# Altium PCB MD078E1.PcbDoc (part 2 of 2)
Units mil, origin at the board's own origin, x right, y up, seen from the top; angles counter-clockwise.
Board outline 4255 x 2850 mil, 4 copper layers (Top Layer, Ground, Power, Bottom Layer), stack 61.6 mil thick; 156 components, 78 nets, 386 pads, 392 vias.
Unrouted connection lines stored in the file: 8.

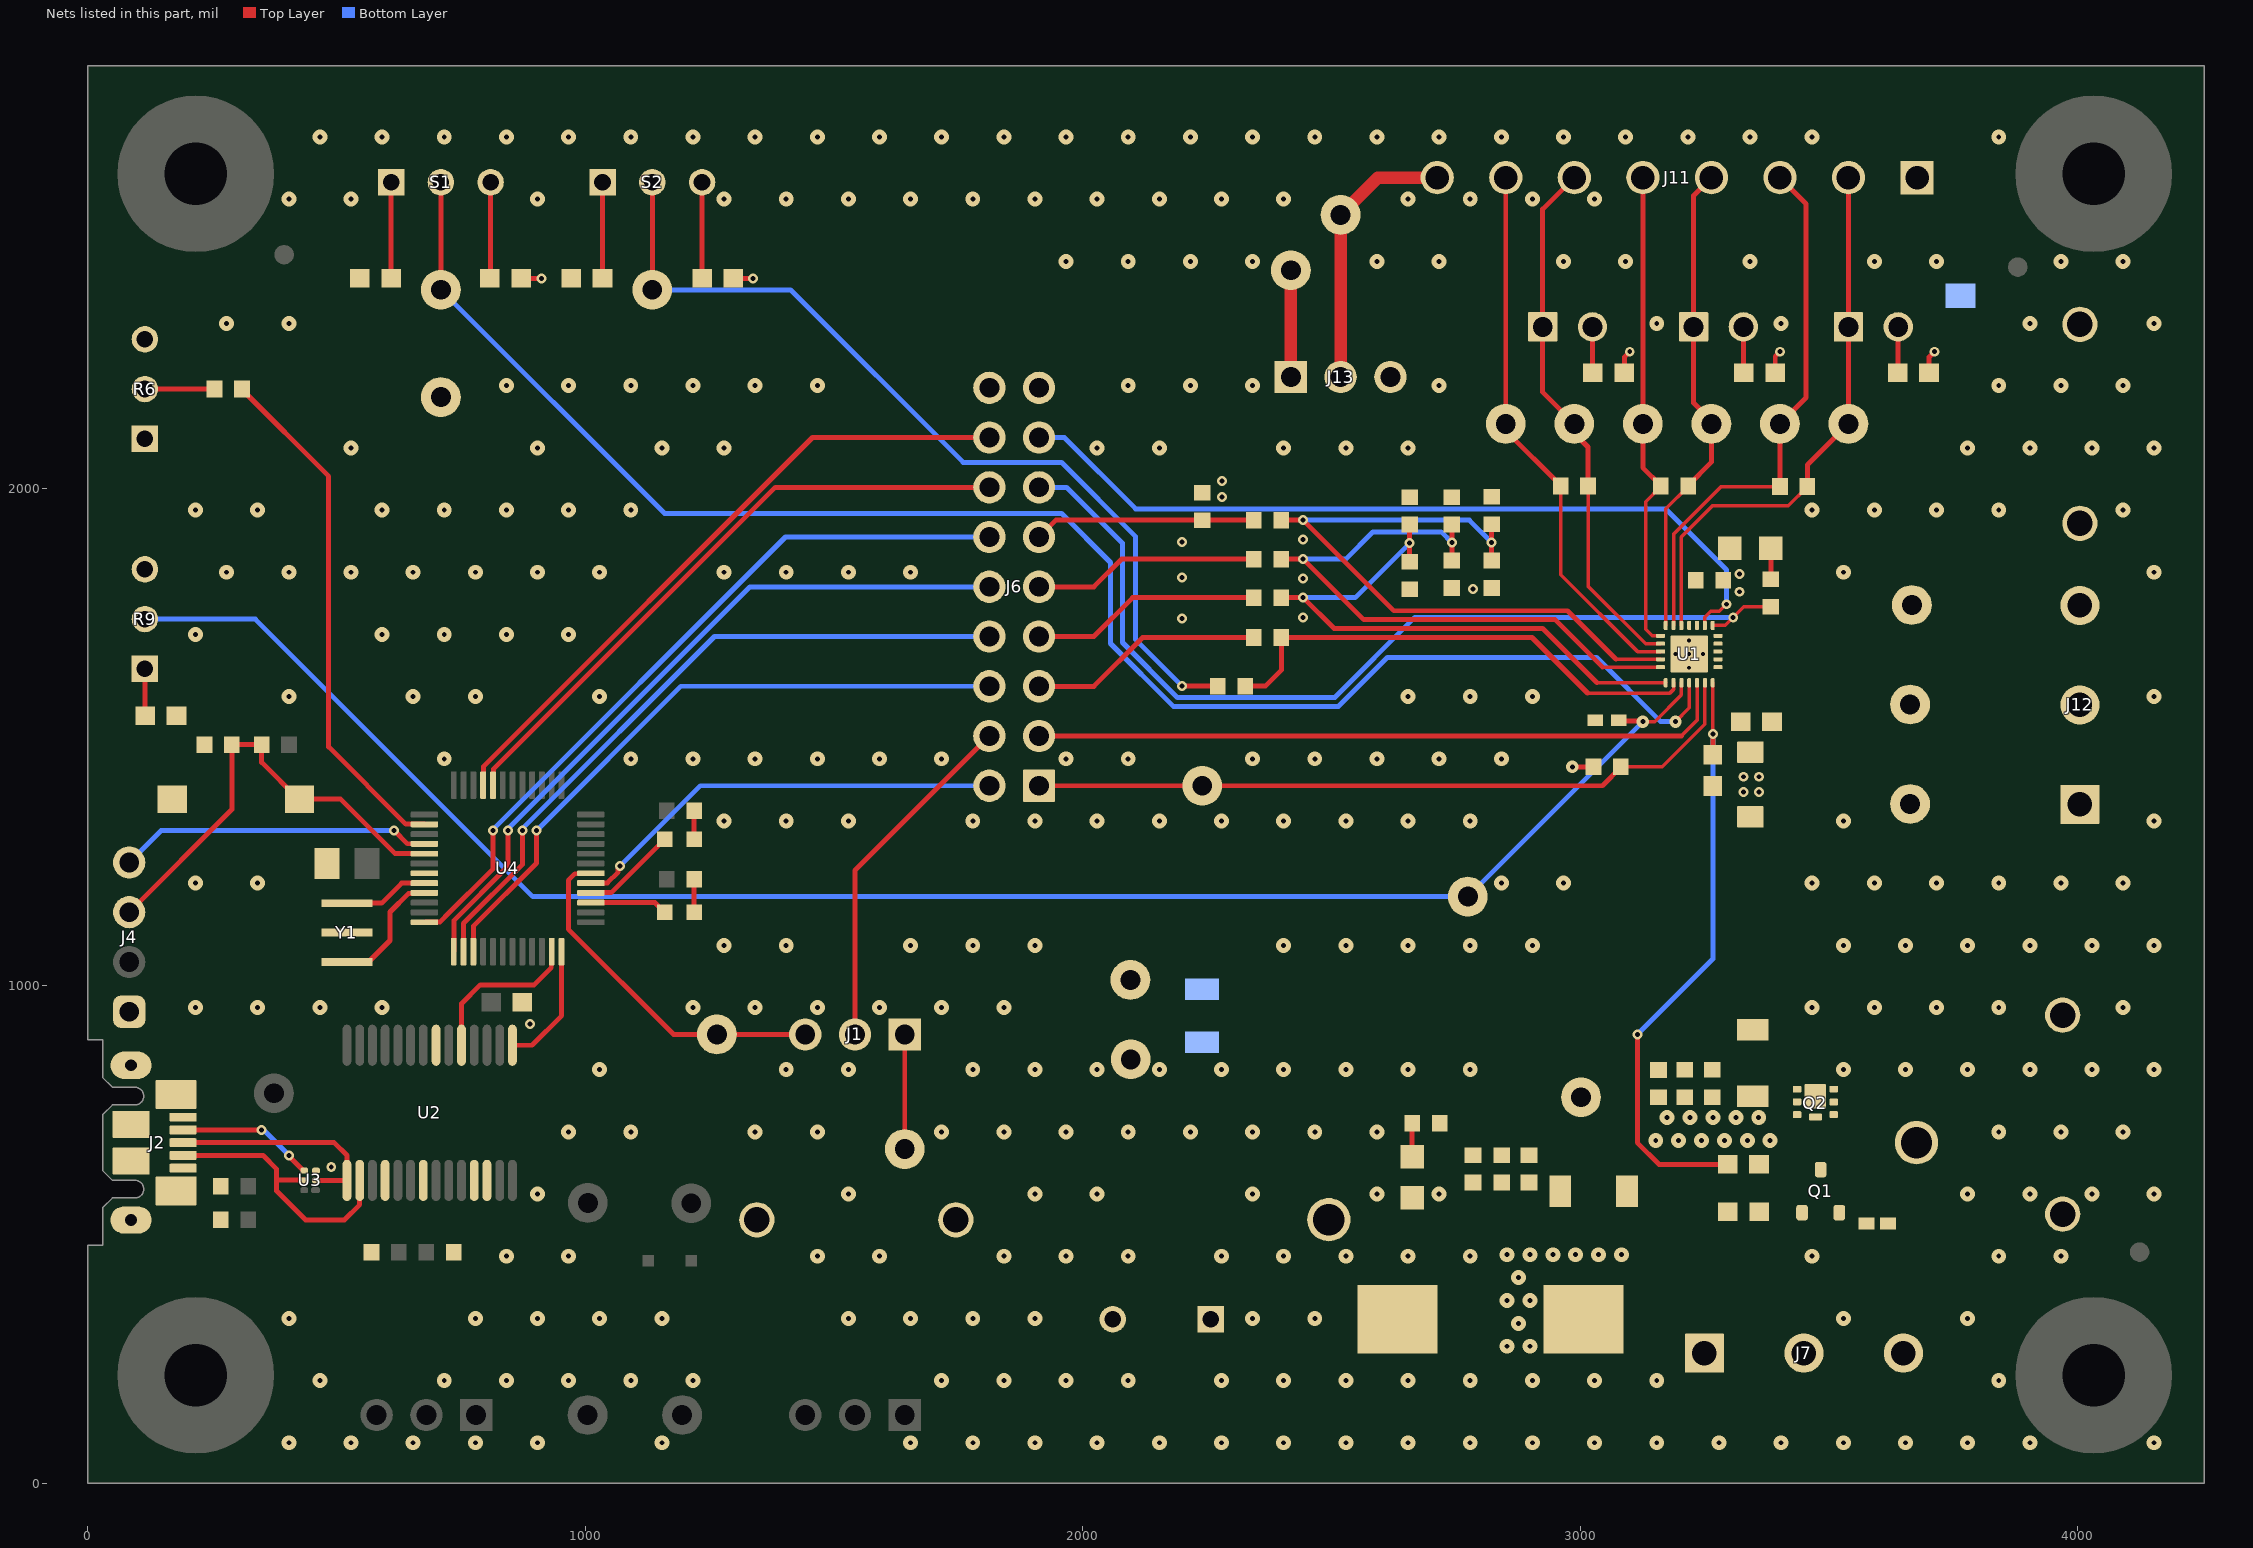
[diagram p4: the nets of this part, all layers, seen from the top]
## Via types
v1: diameter 30, hole 10, Top Layer to Bottom Layer, tented both sides, 335 vias
v2: diameter 20, hole 10, Top Layer to Bottom Layer, 30 vias
v3: diameter 20, hole 10, Top Layer to Bottom Layer, tented both sides, 19 vias
v4: diameter 19.68, hole 7.87, Top Layer to Bottom Layer, tented both sides, 5 vias
v5: diameter 25, hole 10, Top Layer to Bottom Layer, 3 vias

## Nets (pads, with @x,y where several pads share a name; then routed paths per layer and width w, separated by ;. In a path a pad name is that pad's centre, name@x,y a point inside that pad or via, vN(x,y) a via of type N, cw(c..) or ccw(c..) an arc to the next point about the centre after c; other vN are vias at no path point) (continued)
AGND: C1.2 C5.2 C6.2 C7.2 C8.1 C9.2 C10.2 C11.2 J2.5 J2.6 J2.7 J2.8 J2.9 J2.10 J2.11 J4.1 J6.17 J6.18 J11.1 NT1.1 R4.1 R5.1 R6.3 R15.1 R21.1 R22.1 R23.1 R32.1 S3.2 TP18.1 TP18.2 TP23.1 TP24.1 U1.16 U1.25 U2.7 U2.18 U2.21 U2.25 U2.26 U3.3 U4.7 Y1.2
  other v1: 404.27,81.7 529.27,81.7 654.27,81.7 779.27,81.7 904.27,81.7 1154.27,81.7 1654.27,81.7 1779.27,81.7 466.77,206.7 716.77,206.7 841.77,206.7 966.77,206.7 1091.77,206.7 1216.77,206.7 1716.77,206.7 1841.77,206.7 404.27,331.7 779.27,331.7 904.27,331.7 1029.27,331.7 1154.27,331.7 1529.27,331.7 1654.27,331.7 1779.27,331.7 841.77,456.7 966.77,456.7 1466.77,456.7 1591.77,456.7 1841.77,456.7 904.27,581.7 1529.27,581.7 966.77,706.7 1091.77,706.7 1341.77,706.7 1466.77,706.7 1716.77,706.7 1841.77,706.7 1029.27,831.7 1404.27,831.7 1529.27,831.7 1779.27,831.7 216.77,956.7 341.77,956.7 466.77,956.7 591.77,956.7 1216.77,956.7 1341.77,956.7 1466.77,956.7 1591.77,956.7 1716.77,956.7 1841.77,956.7 1279.27,1081.7 1404.27,1081.7 1654.27,1081.7 1779.27,1081.7 1904.27,1081.7 2404.27,1081.7 2529.27,1081.7 2654.27,1081.7 2779.27,1081.7 2904.27,1081.7 216.77,1206.7 341.77,1206.7 2841.77,1206.7 2966.77,1206.7 1279.27,1331.7 1404.27,1331.7 1529.27,1331.7 1779.27,1331.7 1904.27,1331.7 2029.27,1331.7 2154.27,1331.7 2279.27,1331.7 2404.27,1331.7 2529.27,1331.7 2654.27,1331.7 2779.27,1331.7 716.77,1456.7 1091.77,1456.7 1216.77,1456.7 1341.77,1456.7 1466.77,1456.7 1591.77,1456.7 1716.77,1456.7 1966.77,1456.7 2091.77,1456.7 2341.77,1456.7 2466.77,1456.7 2591.77,1456.7 2716.77,1456.7 2841.77,1456.7 404.27,1581.7 654.27,1581.7 779.27,1581.7 1029.27,1581.7 2654.27,1581.7 2779.27,1581.7 2904.27,1581.7 216.77,1706.7 591.77,1706.7 716.77,1706.7 841.77,1706.7 966.77,1706.7 279.27,1831.7 404.27,1831.7 529.27,1831.7 654.27,1831.7 779.27,1831.7 904.27,1831.7 1029.27,1831.7 1279.27,1831.7 1404.27,1831.7 1529.27,1831.7 1654.27,1831.7 216.77,1956.7 341.77,1956.7 591.77,1956.7 716.77,1956.7 841.77,1956.7 966.77,1956.7 1091.77,1956.7 3466.77,1956.7 529.27,2081.7 904.27,2081.7 1154.27,2081.7 1279.27,2081.7 2029.27,2081.7 2154.27,2081.7 2404.27,2081.7 2529.27,2081.7 2654.27,2081.7 841.77,2206.7 966.77,2206.7 1091.77,2206.7 1216.77,2206.7 1341.77,2206.7 1466.77,2206.7 2091.77,2206.7 2216.77,2206.7 2341.77,2206.7 2716.77,2206.7 279.27,2331.7 404.27,2331.7 3154.27,2331.7 3404.27,2331.7 1966.77,2456.7 2091.77,2456.7 2216.77,2456.7 2341.77,2456.7 2591.77,2456.7 2716.77,2456.7 2966.77,2456.7 3091.77,2456.7 3341.77,2456.7 3591.77,2456.7 3716.77,2456.7 404.27,2581.7 529.27,2581.7 904.27,2581.7 1279.27,2581.7 1404.27,2581.7 1529.27,2581.7 1654.27,2581.7 1779.27,2581.7 1904.27,2581.7 2029.27,2581.7 2154.27,2581.7 2279.27,2581.7 2404.27,2581.7 2654.27,2581.7 2779.27,2581.7 2904.27,2581.7 3029.27,2581.7 466.77,2706.7 591.77,2706.7 716.77,2706.7 841.77,2706.7 966.77,2706.7 1091.77,2706.7 1216.77,2706.7 1341.77,2706.7 1466.77,2706.7 1591.77,2706.7 1716.77,2706.7 1841.77,2706.7 1966.77,2706.7 2091.77,2706.7 2216.77,2706.7 2341.77,2706.7 2466.77,2706.7 2591.77,2706.7 2716.77,2706.7 2841.77,2706.7 2966.77,2706.7 3091.77,2706.7 3216.77,2706.7 3341.77,2706.7 3466.77,2706.7
  other v2: 2785,1797.93
  other v3: 489.63,636.25 889.18,923.3 2200.08,1739.02 2443.52,1740.3 2443.52,1819.15 2200.08,1821.4 2200.08,1892.72 2443.52,1897.32
  other v4: 3219.5,1639.64 3191.94,1667.2 3219.5,1667.2 3247.06,1667.2 3219.5,1694.76
AVDD: C1.1 D1.1 J13.3 R1.2 R2.2 R6.1 R7.2 R8.2 R9.3 R16.2 R17.2 R18.2 R29.1 R30.1 R31.1 U1.15 | length 263.2
  Top Layer w10: R1.2@871.5,2422.5 v2(912.48,2422.5) ; R2.2@1298.02,2422.52 v2(1337.45,2422.52) ; v5(2984.64,1440.35) R7.2@3026.96,1440.35 ; R31.1@3089,2232.5 3089,2264 v2(3100,2275) ; R30.1@3392.5,2232.5 3392.5,2265.59 v2(3401.91,2275) ; R29.1@3701.5,2232.5 3701.5,2264 v2(3712.5,2275)
  other v3: 3320.41,1792.5 3320.41,1827.74 2280,1982.76 2280,2015
BRAKE: S1.2 TP3.1 U1.4 | length 3323.9
  Top Layer w7: v5(3191.94,1531.45) 3219.5,1559.01 U1.4@3219.5,1609.52
  Top Layer w10: TP3.1@710,2399.51 S1.2@710,2615.63
  Bottom Layer w10: TP3.1@710,2399.51 1159.51,1950 1957.5,1950 2056.28,1851.22 2056.28,1688.32 2182.51,1562.09 2514.47,1562.09 2612.63,1660.26 3033.4,1660.26 3162.2,1531.45 v5(3191.94,1531.45)
CLK: J6.7 R10.1 | length 464.3
  Top Layer w10: J6.7@1912.5,1702.5 2022.5,1702.5 2100.64,1780.64 R10.1@2344.39,1780.64
DIR: R14.1 S2.2 TP4.1 | length 1804.5
  Top Layer w10: TP4.1@1135,2399.51 S2.2@1135,2615.63 ; v2(2200.05,1602.84) R14.1@2272.07,1602.81
  Bottom Layer w10: TP4.1@1135,2399.51 1412.99,2399.51 1760,2052.5 1957.5,2052.5 2106.64,1903.36 2106.64,1696.25 v2(2200.05,1602.84)
DM: J2.2 U2.16 U3.5 | length 551.5
  Top Layer w10: J2.2@191.81,659.41 352.34,659.41 380,631.75 380,609.7 ; U3.5@435.35,609.17 434.83,609.7 380,609.7 ; U2.16@546.75,609.17 546.75,560.33 516.25,529.83 437.83,529.83 380,587.65 380,609.7
DP: J2.3 U2.15 U3.2 | length 452.4
  Top Layer w10: J2.3@191.81,685 495.57,685 521.16,659.41 U2.15@521.16,609.17 U3.2@458.97,609.17
FGOUT: J6.1 R7.1 TP9.1 U1.6 | length 1473.5
  Top Layer w7: R7.1@3082.07,1440.35 3165,1440.35 3251,1526.35 U1.6@3251,1609.52
  Top Layer w10: J6.1@1912.5,1402.5 TP9.1@2240.64,1402.5 3045.21,1402.5 3082.07,1439.37 R7.1@3082.07,1440.35
HALL_EXT: J13.1 TP31.1 | length 214.6
  Top Layer w25: J13.1@2418.77,2224.15 TP31.1@2418.77,2438.75
HALL_PWR: J11.8 J13.2 TP26.1 | length 551.1
  Top Layer w25: J13.2@2518.77,2224.15 TP26.1@2518.77,2550 2593.77,2625 J11.8@2712.93,2625
HNA: C23.1 J11.3 TP29.1 U1.18 | length 1101.1
  Top Layer w7: U1.18@3188,1724.88 3188,1907.74 3284.28,2004.02 C23.1@3401.91,2004.02
  Top Layer w10: C23.1@3401.91,2004.02 TP29.1@3401.91,2130 3454.41,2182.5 3454.41,2572.5 J11.3@3401.91,2625
HNB: C22.1 J11.5 TP27.1 U1.20 | length 970.9
  Top Layer w7: U1.20@3161.82,1703.81 3144.91,1703.81 3131.87,1716.85 3131.87,1973.7 3162.18,2004.02 C22.1@3162.18,2005 C22.1@3162.18,2005.98
  Top Layer w10: J11.5@3126.32,2625 TP27.1@3126.32,2130 3126.32,2041.85 C22.1@3162.18,2005.98
HNC: C21.1 J11.7 TP21.1 U1.22 | length 1108.6
  Top Layer w7: C21.1@2960.96,2005 2960.96,1826.91 3115.56,1672.32 U1.22@3161.82,1672.32
  Top Layer w10: J11.7@2850.73,2625 TP21.1@2850.73,2130 2850.73,2116.22 2960.96,2005.98 C21.1@2960.96,2005
HPA: C23.2 J8.1 J11.2 TP30.1 U1.17 | length 1128.7
  Top Layer w7: U1.17@3203.75,1724.88 3203.75,1902.45 3266.3,1965 3419,1965 3457.03,2003.03 C23.2@3457.03,2004.02
  Top Layer w10: C23.2@3457.03,2004.02 3457.03,2047.38 TP30.1@3539.65,2130 J8.1@3539.65,2325 3539.7,2325.06 J11.2@3539.7,2625
HPB: C22.2 J9.1 J11.4 TP28.1 U1.19 | length 967.8
  Top Layer w7: U1.19@3172.26,1724.88 3172.26,1958.97 3217.3,2004.02 C22.2@3217.3,2005
  Top Layer w10: C22.2@3217.3,2005 3217.3,2005.98 3264.11,2052.8 TP28.1@3264.11,2130 3264.11,2136.21 3228.33,2171.99 J9.1@3228.33,2325 3228.33,2589.21 J11.4@3264.11,2625
HPC: C21.2 J10.1 J11.6 TP22.1 U1.21 | length 1078.9
  Top Layer w7: C21.2@3016.08,2004.02 3016.08,1803.85 3131.87,1688.07 U1.21@3161.82,1688.07
  Top Layer w10: J11.6@2988.52,2625 2925,2561.48 J10.1@2925,2325 2925,2193.52 TP22.1@2988.52,2130 2988.52,2111.06 3016.08,2083.5 C21.2@3016.08,2005 C21.2@3016.08,2004.02
ID: J2.4 U3.4 | length 278.5
  Top Layer w10: J2.4@191.81,710.59 v2(349.65,710.59) ; v2(404.76,659.41) 404.76,657.48 433.38,628.86 U3.4@435.35,628.86
  Bottom Layer w10: v2(349.65,710.59) 353.58,710.59 v2(404.76,659.41)
ILIM: C5.1 R9.2 TP8.1 U1.3 | length 3561.6
  Top Layer w7: v5(3126.32,1531.45) 3150.2,1531.45 3203.75,1585 U1.3@3203.75,1609.52
  Top Layer w10: C5.1@3078.14,1534.17 3079.5,1532.81 3124.96,1532.81 v5(3126.32,1531.45)
  Bottom Layer w10: R9.2@115,1737.5 115.04,1737.46 336.86,1737.46 894.7,1179.63 TP8.1@2774.49,1179.63 v5(3126.32,1531.45)
MSP_CLK_P4.5: J6.8 U4.14 | length 1393.8
  Top Layer w10: U4.14@755.64,1070 755.64,1125.76 873.75,1243.87 v2(873.75,1312.5)
  Bottom Layer w10: v2(873.75,1312.5) 875.66,1314.41 875.66,1318.01 1260.15,1702.5 J6.8@1812.5,1702.5
MSP_FGOUT_P2.1: J6.2 U4.29 | length 888
  Top Layer w10: U4.29@1010.56,1206.81 1010.94,1207.19 1044.7,1207.19 1066.32,1228.81 1066.32,1234.65 1069.72,1238.06 v2(1069.72,1240.76)
  Bottom Layer w10: v2(1069.72,1240.76) 1231.46,1402.5 J6.2@1812.5,1402.5
MSP_LED0_P2.2: D4.2 U4.28 | length 194.2
  Top Layer w10: U4.28@1010.56,1187.13 1010.9,1187.47 1052.32,1187.47 D4.2@1160,1295.15
MSP_LED1_P2.3: D5.2 U4.27 | length 157.5
  Top Layer w10: U4.27@1010.56,1167.44 1140.6,1167.44 D5.2@1160,1148.04
MSP_nFAULT_P3.3: J6.14 U4.44 | length 1265.2
  Top Layer w10: U4.44@814.69,1402.68 815.6,1403.58 815.6,1435.86 1382.24,2002.5 J6.14@1812.5,2002.5
MSP_nSLEEP_P3.2: J6.16 U4.45 | length 1329.6
  Top Layer w10: U4.45@795.01,1402.68 795.91,1403.58 795.91,1441.45 1456.96,2102.5 J6.16@1812.5,2102.5
MSP_POT_P1.1: R3.1 U4.2 | length 1049.6
  Top Layer w10: R3.1@310.06,2200 310.06,2199.02 484.41,2024.66 484.41,1480.56 639.7,1325.27 677.53,1325.27 U4.2@677.88,1324.92
MSP_PWM_P2.0: J1.3 TP1.1 U4.30 | length 712.2
  Top Layer w10: U4.30@1010.56,1226.5 1009.65,1225.59 979.39,1225.59 966.27,1212.46 966.27,1114.29 1178.06,902.5 TP1.1@1264.93,902.5 J1.3@1442.5,902.5
MSP_RX_P4.3: U2.5 U4.23 | length 327.7
  Top Layer w10: U2.5@751.48,880.83 751.48,964.56 789.27,1002.35 897.53,1002.35 931.9,1036.72 931.9,1069.09 U4.23@932.8,1070
MSP_SBWTCK: J4.4 U4.4 | length 632.2
  Top Layer w10: v2(616.08,1312.5) 642.69,1285.9 677.53,1285.9 U4.4@677.88,1285.55
  Bottom Layer w10: J4.4@83.45,1248.24 147.71,1312.5 v2(616.08,1312.5)
MSP_SBWTDIO/nRST: C10.1 J4.3 R24.1 S3.1 U4.5 | length 922.4
  Top Layer w10: J4.3@83.45,1148.24 289.91,1354.71 C10.1@289.91,1485.08 R24.1@349.65,1485.08 349.65,1449.58 423.78,1375.44 S3.1@425.75,1375.44 508.66,1375.44 618.24,1265.87 677.88,1265.87 U4.5@677.53,1266.21
MSP_SIMO_P4.6: J6.10 U4.13 | length 1460.2
  Top Layer w10: U4.13@735.95,1070 735.95,1131.35 845,1240.4 v2(845,1312.5)
  Bottom Layer w10: v2(845,1312.5) 846.91,1314.41 846.91,1318.02 1331.4,1802.5 J6.10@1812.5,1802.5
MSP_SOMI_P4.7: J6.12 U4.12 | length 1502
  Top Layer w10: U4.12@677.88,1128.07 678.78,1128.98 708.75,1128.98 718.08,1138.3 718.08,1138.76 815.04,1235.72 v2(815.04,1312.5)
  Bottom Layer w10: v2(815.04,1312.5) 815.04,1314.89 1402.65,1902.5 J6.12@1812.5,1902.5
MSP_STE_P4.4: J6.6 U4.15 | length 1325.3
  Top Layer w10: U4.15@775.32,1070 775.32,1120.17 902.5,1247.35 v2(902.5,1312.5)
  Bottom Layer w10: v2(902.5,1312.5) 1192.5,1602.5 J6.6@1812.5,1602.5
MSP_TX_P4.2: U2.1 U4.24 | length 253.2
  Top Layer w10: U2.1@853.84,880.83 893.21,880.83 952.68,940.3 U4.24@952.49,1070
MSP_XIN_P2.7: U4.8 Y1.1 | length 173.5
  Top Layer w10: Y1.1@521.16,1166.35 590.82,1166.35 631.28,1206.81 U4.8@677.88,1206.81
MSP_XOUT_P2.6: U4.9 Y1.3 | length 247.3
  Top Layer w10: Y1.3@521.16,1048.24 564.47,1048.24 607.68,1091.45 607.68,1148.76 645.15,1186.22 675.99,1186.22 U4.9@676.9,1187.13 ; U4.9@677.53,1186.78 U4.9@677.88,1187.13
NetC13_1: C13.1 C14.1 C15.1 C16.1 L2.1 Q2.1 Q2.2 Q2.5 Q2.6 Q2.7
  other v1: 2853.27,275.7 2899.27,275.7 2876.27,321.7 2853.27,367.7 2899.27,367.7 2876.27,413.7 2853.27,459.7 2899.27,459.7 2945.27,459.7 2991.27,459.7 3037.27,459.7 3083.27,459.7 3152.27,689.7 3198.27,689.7 3244.27,689.7 3290.27,689.7 3336.27,689.7 3382.27,689.7 3175.27,735.7 3221.27,735.7 3267.27,735.7 3313.27,735.7 3359.27,735.7
NetD1_2: D1.2 R19.2 | length 62.4
  Top Layer w10: R19.2@3383.78,1817.56 D1.2@3383.78,1880
NetD2_2: D2.2 R20.2 | length 67.7
  Top Layer w10: D2.2@2662.52,656.45 2662.52,723.91 R20.2@2662.72,724.11
NetD4_1: D4.1 R25.1 | length 57.4
  Top Layer w10: D4.1@1219.07,1295.17 R25.1@1219.07,1352.5
NetD5_1: D5.1 R26.1 | length 66.2
  Top Layer w10: D5.1@1219.07,1148.06 R26.1@1219.07,1214.26
NetD6_2: D6.2 Q1.2
NetJ2_1: J2.1 L1.2
NetJ8_2: J8.2 R29.2 | length 93
  Top Layer w10: R29.2@3638.5,2232.5 3639.65,2233.65 J8.2@3639.65,2325
NetJ9_2: J9.2 R30.2 | length 93
  Top Layer w10: J9.2@3328.33,2325 3328.33,2233.68 R30.2@3329.51,2232.5
NetJ10_2: J10.2 R31.2 | length 92.9
  Top Layer w10: J10.2@3025,2325 3025,2233.5 R31.2@3026,2232.5
NetQ1_1: Q1.1 R28.2
NetQ1_3: Q1.3 Q2.3 R27.2
NetR1_1: R1.1 S1.3 | length 193.7
  Top Layer w10: R1.1@808.5,2422.5 810,2424 S1.3@810,2615.63
NetR2_1: R2.1 S2.3 | length 193.1
  Top Layer w10: R2.1@1235,2422.55 S2.3@1235,2615.63
NetR3_2: R3.2 R6.2 | length 139.9
  Top Layer w10: R6.2@115,2200 R3.2@254.94,2200
NetR4_2: R4.2 S1.1 | length 193.2
  Top Layer w10: R4.2@609.9,2422.48 610,2422.58 S1.1@610,2615.63
NetR5_2: R5.2 S2.1 | length 193.1
  Top Layer w10: R5.2@1034.96,2422.52 1035,2422.57 S2.1@1035,2615.63
NetR9_1: R9.1 R15.2 | length 94.4
  Top Layer w10: R9.1@115,1637.5 115,1543.87 R15.2@115.52,1543.35
nFAULT: J6.13 R19.1 U1.13 | length 1886.8
  Top Layer w7: U1.13@3266.74,1724.88 3291.94,1724.88 3329.51,1762.44 R19.1@3383.78,1762.44
  Bottom Layer w10: J6.13@1912.5,2002.5 1967.81,2002.5 2080.24,1890.07 2080.24,1690.3 2190.57,1579.97 2507.06,1579.97 2668.03,1740.93 v2(3308,1740.93)
nSCS/DIR: R13.2 R14.2 U1.2 | length 1002.6
  Top Layer w7: 3015.13,1588.9 3180.84,1588.9 3188,1596.06 U1.2@3188,1609.52
  Top Layer w10: R14.2@2327.19,1602.81 2367.47,1602.81 2399.51,1634.85 R13.2@2399.51,1700.64 2903.39,1700.64 3015.13,1588.9
nSLEEP: J6.15 U1.14 | length 1631.8
  Top Layer w7: U1.14@3251,1724.88 3251,1740.93 3262.97,1752.9 3279.89,1752.9 3294.35,1767.36 v2(3294.43,1767.36)
  Bottom Layer w10: J6.15@1912.5,2102.5 1963.28,2102.5 2106.64,1959.14 2106.71,1959.21 3171.78,1959.21 3294.43,1836.56 v2(3294.43,1767.36)
OUTA: J12.1 TP5.1 U1.10
OUTB: J12.2 TP6.1 U1.11
OUTC: J12.3 TP7.1 U1.12
PGND: C3.1 C4.2 C12.2 C13.2 C14.2 C15.2 C16.2 C17.2 C18.2 C19.2 C20.2 J7.2 NT1.2 R20.1 R28.1 R32.2 TP17.1 TP19.1 TP19.2 TP20.1 TP20.2 TP25.1 U1.9
  other v1: 1904.27,81.7 2029.27,81.7 2154.27,81.7 2279.27,81.7 2404.27,81.7 2529.27,81.7 2654.27,81.7 2779.27,81.7 2904.27,81.7 3029.27,81.7 3154.27,81.7 3279.27,81.7 3404.27,81.7 3529.27,81.7 3654.27,81.7 3779.27,81.7 3904.27,81.7 4154.27,81.7 1966.77,206.7 2091.77,206.7 3841.77,206.7 1904.27,331.7 3529.27,331.7 3779.27,331.7 1966.77,456.7 2091.77,456.7 3466.77,456.7 3841.77,456.7 3966.77,456.7 1904.27,581.7 2029.27,581.7 3779.27,581.7 3904.27,581.7 4029.27,581.7 4154.27,581.7 1966.77,706.7 2091.77,706.7 2216.77,706.7 2341.77,706.7 2466.77,706.7 2591.77,706.7 3841.77,706.7 3966.77,706.7 4091.77,706.7 1904.27,831.7 2029.27,831.7 2154.27,831.7 2279.27,831.7 2404.27,831.7 2529.27,831.7 2654.27,831.7 2779.27,831.7 3529.27,831.7 3654.27,831.7 3779.27,831.7 3904.27,831.7 4029.27,831.7 4154.27,831.7 3466.77,956.7 3591.77,956.7 3716.77,956.7 3841.77,956.7 4091.77,956.7 3529.27,1081.7 3654.27,1081.7 3779.27,1081.7 3904.27,1081.7 4029.27,1081.7 4154.27,1081.7 3466.77,1206.7 3591.77,1206.7 3716.77,1206.7 3841.77,1206.7 3966.77,1206.7 4091.77,1206.7 3529.27,1331.7 4154.27,1331.7 4154.27,1581.7 3529.27,1831.7 4154.27,1831.7 3591.77,1956.7 3716.77,1956.7 3841.77,1956.7 4091.77,1956.7 3779.27,2081.7 3904.27,2081.7 4029.27,2081.7 4154.27,2081.7 3841.77,2206.7 3966.77,2206.7 4091.77,2206.7 3904.27,2331.7 4154.27,2331.7 3966.77,2456.7 4091.77,2456.7 3841.77,2706.7
PWM: J6.3 U1.5 | length 1411.3
  Top Layer w7: 3203.75,1502.5 3235.25,1534 U1.5@3235.25,1609.52
  Top Layer w10: J6.3@1912.5,1502.5 3203.75,1502.5
PWM_EXT: J1.1 TP2.1 | length 230.3
  Top Layer w10: TP2.1@1642.5,672.2 J1.1@1642.5,902.5
PWM_SEL: J1.2 J6.4 | length 711.8
  Top Layer w10: J1.2@1542.5,902.5 1542.5,1232.5 J6.4@1812.5,1502.5
SCLK/ADVANCE: R10.2 R16.1 R21.2 U1.1 | length 1178.2
  Top Layer w7: 3034,1609.52 U1.1@3172.26,1609.52
  Top Layer w10: R10.2@2399.5,1780.64 v3(2443.52,1780.64) 2505.35,1718.81 2505.35,1718.52 2925,1718.52 3034,1609.52 ; R21.2@2657.5,1852.5 v2(2657.5,1890.07) R16.1@2657.5,1927.64
  Bottom Layer w10: v3(2443.52,1780.64) 2548.07,1780.64 v2(2657.5,1890.07)
SDI/FGSEL/LOCK_DET_TIME: R11.2 R17.1 R22.2 U1.24 | length 1255.3
  Top Layer w7: 3045.57,1640.82 U1.24@3161.82,1640.82
  Top Layer w10: R11.2@2399.5,1858.14 v3(2443.52,1858.14) 2565.27,1736.39 2950,1736.39 3045.57,1640.82 ; R22.2@2742.5,1855.3 v2(2742.5,1891.47) R17.1@2742.5,1927.64
  Bottom Layer w10: v3(2443.52,1858.14) 2529.2,1858.14 2584,1912.94 2721.03,1912.94 v2(2742.5,1891.47)
SDO/MODE: R12.2 R18.1 R23.2 U1.23 | length 1348.4
  Top Layer w7: 3072.7,1656.57 U1.23@3161.82,1656.57
  Top Layer w10: R12.2@2399.5,1936.33 v3(2443.52,1936.33) 2625.58,1754.27 2975,1754.27 3072.07,1657.19 3072.7,1657.19 ; R23.2@2822.5,1855.3 v2(2822.5,1891.47) R18.1@2822.5,1928.14
  Bottom Layer w10: v3(2443.52,1936.33) 2777.64,1936.33 v2(2822.5,1891.47)
SIMO: J6.9 R11.1 | length 454.9
  Top Layer w10: J6.9@1912.5,1802.5 2022.5,1802.5 2078.14,1858.14 R11.1@2344.39,1858.14
SOMI: J6.11 R8.1 R12.1 | length 445.9
  Top Layer w10: J6.11@1912.5,1902.5 1946.36,1936.36 R8.1@2240.61,1936.36 R12.1@2344.39,1936.33
STE: J6.5 R13.1 | length 472.8
  Top Layer w10: J6.5@1912.5,1602.5 1912.76,1602.24 2022.5,1602.24 2120.9,1700.64 R13.1@2344.39,1700.64
VBAT: D6.1 J7.3 Q2.4 Q2.8 TP15.1
VCP: C2.2 R27.1 U1.7 | length 1228.3
  Top Layer w7: U1.7@3266.74,1609.52 3266.74,1506.41 v2(3266.91,1506.24)
  Top Layer w10: v2(3115.18,902.5) 3115.18,685 3158.7,641.48 R27.1@3296.83,641.48 ; C2.2@3266.91,1465.04 v2(3266.91,1506.24)
  Bottom Layer w10: v2(3115.18,902.5) 3266.91,1054.23 v2(3266.91,1506.24)
VM: C2.1 C3.2 C4.1 C12.1 C17.1 C18.1 C19.1 C20.1 D2.1 J7.1 L2.2 TP16.1 U1.8
  other v1: 2279.27,206.7 2404.27,206.7 2529.27,206.7 2654.27,206.7 2779.27,206.7 2904.27,206.7 3029.27,206.7 3154.27,206.7 2341.77,331.7 2466.77,331.7 2279.27,456.7 2404.27,456.7 2529.27,456.7 2654.27,456.7 2779.27,456.7 2341.77,581.7 2591.77,581.7 2716.77,581.7
  other v2: 3328.33,1390 3360,1390 3328.33,1420.58 3360,1420.58
pads on no net: FID1.1 FID2.1 FID3.1 H1.1 H2.1 H3.1 H4.1 H5.0 H6.0 H7.0 H8.0 LBL1.0 SH-J1.0 SH-J2.0 SH-J3.0 SH-J4.0 SH-J5.0 SH-J6.0 SH-J7.0 SH-J8.0 SH-J9.0 SH-J10.0 SH-J11.0 SH-J12.0 SH-J13.0 SH-J14.0 SH-J15.0 SH-J16.0 U2.2 U2.3 U2.6 U2.8 U2.9 U2.10 U2.11 U2.12 U2.13 U2.14 U2.19 U2.22 U2.23 U2.24 U2.27 U2.28 U3.1 U4.1 U4.3 U4.10 U4.11 U4.16 U4.17 U4.18 U4.19 U4.20 U4.21 U4.22 U4.25 U4.26 U4.31 U4.32 U4.33 U4.34 U4.35 U4.36 U4.37 U4.38 U4.39 U4.40 U4.41 U4.42 U4.43 U4.46 U4.47 U4.48

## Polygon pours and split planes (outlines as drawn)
AVDD on Top Layer "TOP_LAYER_AVDD_P061" (solid, pour order 61): 2850.73,2030 2850.73,1965 2217.5,1965 2217.5,2030
VM on Top Layer "TOP_LAYER_VM_P053" (solid, remove dead copper, pour order 53): 3240,1645.83 3240,1370 3379.84,1370 3379.84,1505 3351.12,1505 3351.12,1575.32 3302.24,1575.32 3302.24,1645.83
OUTA on Top Layer "TOP_LAYER_OUTA_P057" (solid, pour order 57): 3265,1677.5 3265,1667.5 3350,1667.5 3600,1275 4120,1275 4120,1475 3600,1475 3372.71,1677.5
AVDD on Top Layer "TOP_LAYER_AVDD_P065" (solid, remove dead copper, pour order 65): 3262.04,1792.5 3230,1792.5 3230,1715 3250,1715 3250,1740 3294.43,1740 3294.43,1775 3352.28,1775 3352.28,1907.5 3262.04,1907.5
OUTB on Top Layer "TOP_LAYER_OUTB_P058" (solid, pour order 58): 3265,1700 3428.89,1700 3600,1675 4120,1675 4120,1475 3600,1475 3372.71,1677.5 3265,1677.5
OUTC on Top Layer "TOP_LAYER_OUTC_P056" (solid, pour order 56): 3265,1710 3460,1725 3600,1875 4120,1875 4120,1675 3600,1675 3460,1700 3265,1700
NetC13_1 on Top Layer "TOP_LAYER_NETC13_1_P046" (solid, pour order 46): 3520,802.5 3130,802.5 3130,650 3422.5,650 3422.5,750 3520,750
NetD6_2 on Top Layer "TOP_LAYER_NETD6_2_P048" (solid, pour order 48): 3497.9,578.68 3497.9,500 3598.21,500 3598.21,578.68
NetC13_1 on Top Layer "TOP_LAYER_NETC13_1_P049" (solid, pour order 49): 2830,490 3100,490 3100,232.5 2830,232.5
PGND on Top Layer "TOP_LAYER_PGND_P070" (solid, remove dead copper, pour order 70): 4255,0 1865,0 1865,939.48 1864.48,940 3266.91,940 3266.91,1712.62 3767.5,2213.21 3767.5,2850 4255,2850
AGND on Top Layer "TOP_LAYER_AGND_P075" (solid, remove dead copper, pour order 75): 0,0 1865,0 1865,939.78 1865.22,940 3266.74,940 3266.74,1712.46 3767.5,2213.21 3767.5,2850 0,2850
AVDD on Top Layer "TOP_LAYER_AVDD_P066" (solid, pour order 66): 80,2132.5 150,2132.5 150,1802.5 80,1802.5
NetQ1_1 on Top Layer "TOP_LAYER_NETQ1_1_P045" (solid, pour order 45): 3322.91,578.68 3322.91,500 3492.61,500 3492.61,578.68
VBAT on Top Layer "TOP_LAYER_VBAT_P054" (solid, remove dead copper, pour order 54): 3605,580 3450,580 3450,802.5 3752.5,802.5 3752.5,172.5 3605,172.5
NetQ1_3 on Top Layer "TOP_LAYER_NETQ1_3_P047" (solid, remove dead copper, pour order 47): 3322.91,685 3322.91,584.04 3517.5,584.04 3517.5,685 3450,685 3450,750 3422.5,750 3422.5,685
VM on Top Layer "TOP_LAYER_VM_P050" (solid, pour order 50): 2170,625 3000,625 3000,277.5 3187.5,277.5 3187.5,330 3317.5,330 3317.5,122.5 2170,122.5
5VCC on Top Layer "TOP_LAYER_5VCC_P055" (solid, pour order 55): 605,490 705,490 705,442.5 605,442.5
NetJ2_1 on Top Layer "TOP_LAYER_NETJ2_1_P044" (solid, remove dead copper, pour order 44): 170,650 340,650 340,565 170,565
5V_USB on Top Layer "TOP_LAYER_5V_USB_P043" (solid, pour order 43): 305,617.5 305,490 390,490 390,617.5
NetC13_1 on Bottom Layer "BOTTOM_LAYER_NETC13_1_P073" (solid, pour order 73): 2830,232.5 3155,232.5 3155,592.5 3422.5,592.5 3422.5,822.5 3130,822.5 3130,706.97 2830,706.97
AGND on Bottom Layer "BOTTOM_LAYER_AGND_P076" (solid, remove dead copper, pour order 76): 0,2850 3767.5,2850 3767.5,2203.16 3276.25,1711.91 3276.33,1047.64 3168.69,940 1865,940 1865,0 0,0
PGND on Bottom Layer "Bottom Layer-PGND" (solid, remove dead copper, pour order 74): 1865,940 1865,0 4255,0 4255,2850 3767.5,2850 3767.5,2203.16 3276.25,1711.91 3276.25,1049.4 3161.08,940
5V_USB on Bottom Layer "BOTTOM_LAYER_5V_USB_P071" (solid, pour order 71): 440,495 315,495 315,840.51 440,840.51
AVDD on Power "POWER_AVDD_P067" (solid, pour order 67): 2959.26,1420.58 3012.63,1420.58 3012.63,1775 3352.28,1775 3352.28,2057.5 3757.5,2057.5 3757.5,2290.5 2864.88,2290.5 2739.8,2387.5 1879.47,2387.5 1783.18,2490 672.5,2490 320,2137.5 80,2137.5 80,2065 370.4,2065 612.34,2302.5 1835,2302.5 2252.5,2302.5 2252.5,1963.92 2307.5,1963.92 2307.5,2302.5 2575,2302.5 2575,2174.15 2662.5,2174.15 2662.5,2302.5 2700,2302.5 2785,2235 2785,2057.5 3262.04,2057.5 3262.04,1850 2959.26,1850
AGND on Power "POWER_AGND_P069" (solid, remove dead copper, pour order 69): 0,2850 0,0 4255,0 4255,2850
VM on Power "POWER_VM_P064" (solid, pour order 64): 2707.5,630 2170,630 2170,122.5 3387.5,122.5 3387.5,1477.5 3045,1477.5 3045,1015
5V_USB on Power "POWER_5V_USB_P063" (solid, pour order 63): 315,617.5 440,617.5 440,495 315,495
3V3_MCU on Power "POWER_3V3_MCU_P062" (solid, pour order 62): 1495,85 1595,85 1595,206.16 1272.5,526.21 1272.5,815 1150.3,937.2 1150.3,1395 1050,1395 1050,1277.5 512.5,1277.5 512.5,1470 415,1470 415,1100 46.93,1100 46.93,1000 512.5,1000 512.5,1180 1050,1180 1050,885 1157.5,777.5 1157.5,495 1495,157.5
AGND on Ground "GROUND_AGND_P072" (solid, remove dead copper, pour order 72): 0,2850 4255,2850 4255,0 0,0

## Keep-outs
Keep-Out Layer:
  text ".Layer_Name" at -201.73,-1117.79 h60

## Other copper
Top Layer:
  text ".Layer_Name" at -201.73,-1117.79 h60
Bottom Layer:
  text ".Layer_Name" at -201.73,-1117.79 h60

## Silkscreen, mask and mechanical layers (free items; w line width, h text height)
Top Overlay:
  lines w8: 505.04,61.69 846.71,61.38 846.96,406.6 505.28,406.91 505.04,63.84 ; 1367.28,62.4 1707.33,62.1 1707.57,412.11 1367.53,412.41 1367.28,64.56 ; 1450,2572.5 1735,2572.5 ; 1450,2637.5 1735,2637.5 ; 1510,2515 1510,2700 ; 1542.36,2667.94 1556.73,2680 ; 1542.77,2667.47 1555.72,2657.5 ; 1543.77,2667.94 1597.33,2667.5 ; 1620,2515 1620,2700 ; 1654.83,2670.33 1708.39,2669.89 ; 1695.43,2657.83 1709.8,2669.89 ; 1696.44,2680.33 1709.39,2670.36 ; 1862.5,2850 1865,7.5 ; 2238.77,1671.43 2238.77,1521.4 2565.99,1521.53 ; 2565.58,1671.75 2131.56,1671.33 2131.56,1821.4 2303.71,1821.4 2303.71,2017.8 2875,2017.8 2876.32,1301.26 3595,1301.26 3600,1925 2876.32,1925 ; 2565.58,2017.8 2565.58,1445.36 2777.5,1445.36 2875.36,1445.36 ; 1366.05,761.65 1366.46,1214.26 1711.68,1214.02 1711.28,761.41 1366.05,761.65 ; 1450,2515 1735,2515 1735,2700 1450,2700 1450,2515 ; 2345.82,2057.66 2346.03,2290.13 2691.25,2289.88 2691.05,2057.41 2345.82,2057.66
  text "HPWR" at 2646.14,2790 h30
  text "HNC" at 2811.14,2790 h30
  text "HPC" at 2951.14,2790 h30
  text "HNB" at 3091.14,2790 h30
  text "HPB" at 3223.64,2790 h30
  text "HNA" at 3366.14,2790 h30
  text "HPA" at 3501.14,2790 h30
  text "AGND" at 3636.14,2790 h30
  text "Switches" at 1479.83,2717.5 h30
  text "S" at 1472.33,2655 h30
  text "1" at 1474.95,2590.08 h30
  text "BRK" at 1524.83,2590.08 h30
  text "RUN" at 1637.33,2590.08 h30
  text "2" at 1469.95,2527.58 h30
  text "ABC" at 1524.83,2527.58 h30
  text "ACB" at 1637.33,2527.58 h30
  text "Analog: connect to HPx and HNx, remove J9-J11" at 2512.44,2447.5 h30
  text "Digital: connect to HPx only, populate J9-J11" at 2512.44,2400 h30
  text "HALL_PWR_SEL" at 2298.77,2322.5 h40
  text "PWM" at 225.2,2255 h40
  text "AGND" at 1621.84,2184.91 h30
  text "AGND" at 2006.86,2184.91 h30
  text "HALL" at 2371.27,2129.13 h30
  text "AVDD" at 2564.58,2127.5 h30
  text "MSP_nSLEEP" at 1442.5,2085.24 h30
  text "nSLEEP" at 2006.86,2085.24 h30
  text "EXT" at 2386.27,2080.24 h30
  text "MSP_nFAULT" at 1442.5,1985.56 h30
  text "nFAULT" at 2006.86,1985.56 h30
  text "SDO" at 2424.74,1923.54 h30
  text "MSP_SOMI" at 1510,1885.88 h30
  text "SOMI" at 2006.86,1885.88 h30
  text "nFAULT" at 3081.79,1864 h30
  text "SDI" at 2424.74,1845.35 h30
  text "ILIM" at 221.19,1805.4 h40
  text "MSP_SIMO" at 1510,1786.21 h30
  text "SIMO" at 2006.86,1786.21 h30
  text "SCLK" at 2424.74,1767.85 h30
  text "Pop." at 2189.83,1758.91 h30
  text "OUTC" at 4219.51,1707.59 h40 r90
  text "if SPI" at 2154.27,1700.64 h30
  text "nSCS" at 2424.74,1687.85 h30
  text "MSP_SCK" at 1532.5,1686.53 h30
  text "SCK" at 2006.86,1686.53 h30
  text "MODE" at 2837.79,1660.26 h30 r90
  text "DIR" at 2352.78,1590.01 h30
  text "MSP_STE" at 1532.5,1586.85 h30
  text "STE" at 2006.86,1586.85 h30
  text "FGSEL/" at 2735.19,1577.58 h30 r90
  text "ADVANCE" at 2672.72,1568.25 h30 r90
  text "L_D_TIME" at 2777.64,1547 h30 r90
  text "Pop. if HW" at 2270.41,1544.35 h30
  text "HW Variant" at 2582.77,1504.25 h30
  text "OUTB" at 4219.51,1490.95 h40 r90
  text "MSP_PWM" at 1532.5,1487.18 h30
  text "PWM" at 2006.86,1487.18 h30
  text "Resistors" at 2597.5,1462.5 h30
  text "MSP_FGOUT" at 1472.5,1387.5 h30
  text "FGOUT" at 2006.86,1387.5 h30
  text "Depop. R10-R13" at 2353.96,1381.48 h30
  text "RST" at 469.95,1358.39 h30
  text "if HW variant" at 2370.28,1328.56 h30
  text "MCT8314Z" at 3564.65,1326.93 h60 r90
  text "OUTA" at 4219.51,1275 h40 r90
  text "SBWTCK" at 170,1235 h30
  text "'.EVM_Orderable'" at 3604.17,1170.89 h50
  text "SBWTDIO" at 170,1135 h30
  text "Rev '.ROM_Rev'" at 3603.17,1107.17 h40
  text "'.PRJ_Number'.PCB_Rev-'.Variant'" at 3602.17,1048.78 h30
  text "3.3V" at 170,1035 h30
  text "PWM_EXT" at 1652.7,991.2 h30 r90
  text "PWM_MSP" at 1456,982.5 h30 r90
  text "GND" at 170,935 h30
  text "PWM_SEL" at 1417.32,785 h40
  text "VM" at 2565,572.48 h30
  text "5V_USB" at 592.14,217.5 h30 r90
  text "5V_EXT" at 794.53,216.76 h30 r90
  text "3V3COM" at 1456,208.24 h30 r90
  text "3V3EXT" at 1657.5,207.5 h30 r90
  text "5V_SEL" at 475.89,125 h40 r90
  text "3V3_SEL" at 1770,112.5 h40 r90
  text "Connect to VM to bypass" at 2342.5,82.5 h35
  text "reverse polarity protection" at 2217.5,35 h35
  text "VM" at 3213.05,32.5 h40
  text "PGND" at 3375,32.5 h40
  text "VBAT" at 3575,32.5 h40
  text ".Layer_Name" at -201.73,-1117.79 h30
Bottom Overlay:
  text "OUTC" at 4207.5,1747.06 h40
  text "OUTC" at 3869.67,1744.25 h40
  text "OUTB" at 3867.5,1547.94 h40
  text "OUTB" at 4207.5,1545 h40
  text "OUTA" at 3867.5,1345 h40
  text "OUTA" at 4207.5,1345 h40
  text "VM" at 3282.5,150 h40
  text "PGND" at 3522.5,150 h40
  text "VBAT" at 3720.3,149.78 h40
  text ".Layer_Name" at -201.73,-1117.79 h60
Top Paste:
  text ".Layer_Name" at -201.73,-1117.79 h60
Bottom Paste:
  text ".Layer_Name" at -201.73,-1117.79 h60
Top Solder:
  text ".Layer_Name" at -201.73,-1117.79 h60
  text ".Layer_Name" at -201.73,-1117.79 h60
Bottom Solder:
  text ".Layer_Name" at -201.73,-1117.79 h60
Drill Guide:
  text ".Layer_Name" at -201.73,-1117.79 h60
M1 Board Outline:
  lines w4: 0,891.69 30,891.69 30,815.91 49.68,796.22 94.96,796.22 cw(c94.85,778.5) 94.96,760.79 49.68,760.79 30,741.1 30,628.9 49.68,609.21 94.96,609.21 cw(c94.85,591.5) 94.96,573.78 49.68,573.78 30,554.09 30,478.31 0,478.31 0,0 4255,0 4255,2850 0,2850 0,892.96 1.27,891.69
  text ".Layer_Name" at -201.73,-1117.79 h60
M2 Board Dimensions:
  rectangle: -778.73,-534.3 -653.73,-409.3
  rectangle: -653.73,-659.3 -278.73,-534.3
  lines w7: -778.73,-534.3 221.27,-534.3 ; -653.73,-659.3 -653.73,-409.3 ; -528.73,-659.3 -528.73,-409.3 ; -278.73,-659.3 -278.73,-409.3 ; -28.73,-659.3 -28.73,-409.3 ; -778.73,-659.3 221.27,-659.3 221.27,-409.3 -778.73,-409.3 -778.73,-659.3
  text ".Layer_Name" at -201.73,-1117.79 h60
M3 3D STEP Top:
  text ".Layer_Name" at -201.73,-1117.79 h60
M4 3D STEP Bottom:
  text ".Layer_Name" at -201.73,-1117.79 h60
M5 Assembly Top:
  lines w10: -1070.73,-1189.46 5529.27,-1189.46 ; -1070.73,-986.13 5531.27,-986.13 ; -1070.73,-782.8 -1070.73,-1392.8 2934.27,-1392.8 5531.27,-1392.8 5531.27,-782.8 -1070.23,-782.8 -1070.23,-1392.8 505.27,-1392.8 ; 1394.27,-1392.8 1394.27,-782.8 ; 2661.27,-986.13 2661.27,-782.8 ; 3501.27,-986.13 3501.27,-782.8 ; 4123.27,-1399.3 4123.27,-1196.46
  text "COMPONENTS MARKED 'DNP' SHOULD NOT BE POPULATED." at 374.77,-577.8 h60
  text "ASSEMBLY VARIANT:" at 374.27,-693.3 h60
  text ".VariantName" at 1410.27,-693.3 h60
  text "PCB VIEWED FROM TOP SIDE" at -1007.23,-914.96 h60
  text "BOARD #:" at 1469.27,-914.96 h60
  text ".PRJ_Number" at 2014.77,-914.96 h60
  text "REV:" at 2859.27,-914.96 h60
  text ".PCB_Rev" at 3150.77,-914.96 h60
  text "SVN REV:" at 3697.27,-914.96 h60
  text ".VersionControl_RevNumber" at 4203.27,-914.96 h60
  text "TID #:" at 1469.27,-1118.3 h60
  text ".TID" at 2014.77,-1118.3 h60
  text "PLOT NAME =" at -1007.23,-1323.63 h60
  text ".plot_File_Name" at -201.73,-1323.63 h60
  text "GENERATED    :" at 1471.27,-1323.63 h60
  text ".Print_Date" at 2340.77,-1323.63 h60
  text ".Print_Time" at 3069.77,-1323.63 h60
  text "TEXAS INSTRUMENTS" at 4334.27,-1323.63 h60
M6 Assembly Bottom:
  lines w10: -1071.23,-986.63 5530.77,-986.63 ; -1069.23,-1189.96 5530.77,-1189.96 ; 336.77,-1399.8 336.77,-1196.96 ; 958.77,-986.63 958.77,-783.3 ; 1798.77,-986.63 1798.77,-783.3 ; 3065.77,-1393.3 3065.77,-783.3 ; 3954.77,-1393.3 5530.27,-1393.3 5530.27,-783.3 -1071.23,-783.3 -1071.23,-1393.3 1525.77,-1393.3 5530.77,-1393.3 5530.77,-783.3
  text "COMPONENTS MARKED 'DNP' SHOULD NOT BE POPULATED." at 5323.27,-577.3 h60
  text ".VariantName" at 4279.27,-693.3 h60
  text "ASSEMBLY VARIANT:" at 5318.27,-693.3 h60
  text ".VersionControl_RevNumber" at 256.77,-915.46 h60
  text "SVN REV:" at 762.77,-915.46 h60
  text ".PCB_Rev" at 1309.27,-915.46 h60
  text "REV:" at 1600.77,-915.46 h60
  text ".PRJ_Number" at 2445.27,-915.46 h60
  text "BOARD #:" at 2990.77,-915.46 h60
  text "PCB VIEWED FROM BOTTOM SIDE" at 5467.27,-915.46 h60
  text ".TID" at 2445.27,-1118.8 h60
  text "TID #:" at 2990.77,-1118.8 h60
  text "TEXAS INSTRUMENTS" at 125.77,-1324.13 h60
  text ".Print_Time" at 1390.27,-1324.13 h60
  text ".Print_Date" at 2119.27,-1324.13 h60
  text "GENERATED    :" at 2988.77,-1324.13 h60
  text ".plot_File_Name" at 4661.77,-1324.13 h60
  text "PLOT NAME =" at 5467.27,-1324.13 h60
M9 Title Sheet:
  drawing of 57 lines, arcs and shapes, not listed
  text "1" at -38.89,7777.2 h70
  text "2" at 2456.77,7777.2 h70
  text "3" at 4946.11,7777.2 h70
  text "4" at 7452.78,7777.2 h70
  text "5" at 9951.77,7777.2 h70
  text "6" at 12456.77,7777.2 h70
  text "A" at -1195.23,6634.2 h70
  text "A" at 13604.77,6634.2 h70
  text "B" at -1195.23,4254.2 h70
  text "B" at 13604.77,4254.2 h70
  text "C" at -1195.23,1879.2 h70
  text "C" at 13604.77,1879.2 h70
  text "PROJECT TITLE:" at 10564.77,18.2 h45
  text ".PRJ_Title" at 10614.77,-115.12 h70
  text "DESIGNED FOR:" at 10564.77,-282.8 h45
  text ".PRJ_Customer" at 10614.77,-422.8 h70
  text "D" at -1195.23,-490.8 h70
  text "D" at 13604.77,-490.8 h70
  text "FILE NAME:" at 10564.77,-582.8 h45
  text ".PCB_File_Name_No_Path" at 10614.77,-702.8 h70
  text "Texas Instruments (TI) and/or its licensors do not warrant the accuracy or completeness of this specification" at 5595.27,-864.63 h45
  text "ENGINEER:" at 10564.77,-872.8 h45
  text "LAYOUT BY:" at 12069.77,-872.8 h45
  text "or any information contained therein. TI and/or its licensors do not warrant that this design will meet" at 5550.28,-977.3 h45
  text ".PRJ_Engineer" at 10614.77,-1027.79 h70
  text ".PCB_Layout" at 12120.27,-1027.79 h70
  text "the specifications, will be suitable for your application or fit for any particular purpose, or will operate in" at 5550.28,-1089.97 h45
  text ".Layer_Name" at -201.73,-1117.79 h60
  text "ALTIUM DESIGNER VERSION:" at 12069.77,-1182.8 h45
  text "an implementation. TI and/or its licensors do not warrant that the design is production worthy. You should" at 5550.28,-1202.63 h45
  text "completely validate and test your design implementation to confirm the system functionality for your application." at 5595.27,-1315.3 h45
  text ".print_Scale" at 10614.77,-1316.12 h70
  text ".Application_BuildNumber" at 12120.27,-1316.12 h70
  text "1" at -38.89,-1522.8 h70
  text "2" at 2456.77,-1522.8 h70
  text "3" at 4946.11,-1522.8 h70
  text "4" at 7452.78,-1522.8 h70
  text "5" at 9951.77,-1522.8 h70
  text "6" at 12456.77,-1522.8 h70
M10 Fab Notes:
  drawing of 189 lines, arcs and shapes, not listed
  text "DESIGN INFORMATION" at 11603.29,6096.88 h60
  text "MIN. TRACK WIDTH:" at 10958.73,5964.75 h60
  text "7" at 12054.97,5964.75 h60
  text "MIL" at 12209.73,5964.75 h60
  text "MIN. CLEARANCE:" at 10958.73,5840.63 h60
  text "0.2" at 11994.97,5840.63 h60
  text "mm" at 12209.73,5840.63 h60
  text "MIN. VIA PAD SIZE:" at 10958.73,5716.5 h60
  text "20" at 12024.98,5716.5 h60
  text "MIL" at 12209.73,5716.5 h60
  text "0.05mm (2MIL)" at 11653.73,5586.6 h60
  text "MINIMUM ANNULAR RING" at 10629.5,5578.38 h60
  text "EXTERNAL" at 12361.73,5578.38 h60
  text "PER" at 10829.5,5468.25 h60
  text "IPC-D-275 CLASS 2 LEVEL C" at 11049.5,5468.25 h60
  text "MIL, HOLES" at 12537.73,5367.77 h60
  text "+/-" at 12145.27,5359.19 h60
  text "+/-" at 12999.27,5359.19 h60
  text "REGISTRATION TOLERANCES:" at 10629.5,5358.12 h60
  text "METAL" at 11829.27,5358.12 h60
  text "5" at 12405.47,5358.12 h60
  text "3" at 13238.47,5358.12 h60
  text "MIL" at 13354.73,5358.12 h60
  text "HOLE SIZE TOLERANCE (UNLESS OTHERWISE SPECIFIED):" at 10629.5,5259.81 h60
  text "+/-" at 12999.27,5256.93 h60
  text "3" at 13238.47,5255.87 h60
  text "MIL" at 13354.73,5255.87 h60
  text "MATERIAL:" at 10554.73,5118.22 h60
  text "FR-4 High Tg" at 11541.17,4989.7 h60
  text "X" at 11396.73,4981.71 h60
  text "FR-408" at 10975.73,4977.19 h60
  text "OTHER" at 12463.73,4977.19 h60
  text "62 MIL (1.6mm) +/-10%" at 11295.83,4834.16 h60
  text "X" at 11175.73,4831.71 h60
  text "THICKNESS:" at 10629.5,4825.94 h60
  text "OTHER" at 12580.73,4825.94 h60
  text "TOLERANCE:" at 10629.5,4687.63 h60
  text "X" at 11477.73,4687.63 h60
  text "ANSI IPC-6012 TYPE 3 CLASS 2" at 11655.75,4687.63 h60
  text "OTHER +/-" at 11655.73,4543.44 h60
  text "BOW & TWIST:" at 10629.5,4398.25 h60
  text "X" at 11477.73,4398.25 h60
  text "ANSI IPC-6012 TYPE 3 CLASS 2" at 11655.75,4398.25 h60
  text "OTHER +/-" at 11655.73,4251.55 h60
  text "DRILLING:" at 10554.73,4120.93 h60
  text "NC_DRILL FILES" at 12315.73,4015.74 h60
  text "REFERENCE:" at 10629.5,4011.81 h60
  text "X" at 11286.73,4011.71 h60
  text "AS SHOWN" at 11464.73,4011.81 h60
  text "X" at 12187.73,4011.81 h60
  text "OTHER" at 12613.73,3869.55 h60
  text "PTH COPPER THICKNESS:" at 10629.18,3866.03 h60
  text "X" at 11768.41,3866.03 h60
  text "20-30 um" at 11896.41,3866.03 h60
  text "BOARD FINISH:" at 10554.73,3718.43 h60
  text "SILKSCREEN:" at 10709.95,3608.3 h60
  text "X" at 11667.73,3608.3 h60
  text "TOP" at 11784.73,3608.3 h60
  text "X" at 12177.73,3608.3 h60
  text "BOTTOM" at 12295.73,3608.3 h60
  text "SILKSCREEN COLOR:" at 10709.95,3453.11 h60
  text "X" at 11666.73,3453.11 h60
  text "WHITE" at 11784.73,3453.11 h60
  text "OTHER" at 12295.73,3453.11 h60
  text "X" at 11797.73,3309.67 h60
  text "GREEN" at 11915.73,3309.67 h60
  text "OTHER" at 12533.73,3309.67 h60
  text "SOLDER RESIST COLOR:" at 10709.95,3302.8 h60
  text "X" at 11797.73,3155.41 h60
  text "MATTE" at 11915.73,3155.41 h60
  text "SEMI-GLOSS" at 12533.27,3154.78 h60
  text "IMMERSION GOLD (ENIG)" at 11615.73,2982.64 h60
  text "ENEPIG" at 12953.27,2975.42 h60
  text "SURFACE FINISH:" at 10554.73,2974.42 h60
  text "X" at 11437.73,2974.42 h60
  text "IMM. TIN/SILVER OR EQUIV" at 10884.27,2837.11 h60
  text "OTHER" at 12315.73,2833.17 h60
  text "ARRAY/PANEL:" at 10554.73,2677.79 h60
  text "CUT AND TRIM PER M1 BOARD OUTLINE" at 11615.73,2669.57 h60
  text "N.C. ROUTE" at 11615.73,2533.6 h60
  text "X" at 12303.73,2533.6 h60
  text "V. SCORE" at 12481.73,2533.6 h60
  text "CERTIFICATION:" at 10554.73,2404.48 h60
  text "MATERIALS AND WORKMANSHIP FOR ALL PCBS" at 11279.73,2404.48 h60
  text "TO MEET OR EXCEED THE REQUIREMENTS OF:" at 11279.73,2310.41 h60
  text "X" at 10917.24,2181.78 h60
  text "ANSI IPC-A-600F CLASS ->" at 11045.23,2181.78 h60
  text "X" at 12693.24,2181.78 h60
  text "2" at 12803.23,2181.78 h60
  text "1" at 12488.23,2180.29 h60
  text "3" at 13157.23,2180.29 h60
  text "X" at 11729.24,2034.1 h60
  text "RoHS" at 11857.23,2034.1 h60
  text "OTHER" at 12501.63,2034.1 h60
  text "PER ORDER" at 12898.69,2034.1 h60
  text "ALL BOARDS MUST MEET OR EXCEED UL94-V0 REQUIREMENTS." at 10582.27,1880.27 h60
  text "PCB MUST BEAR THE UL94V-0 UL REGISTERED MATERIAL ID NUMBER" at 10582.27,1764.21 h60
  text "ADDITIONAL REQUIREMENTS:" at 10554.73,1594.78 h60
  text "MICROSECTION:" at 10629.5,1487.66 h60
  text "YES" at 11535.23,1487.66 h60
  text "REQUIRED" at 12396.73,1343.32 h60
  text "BARE BOARD ELEC. TEST:" at 10629.5,1340.47 h60
  text "NONE" at 11935.23,1340.47 h60
  text "X" at 12278.73,1340.47 h60
  text "PER ORDER" at 12988.73,1340.47 h60
  text "XX MIL VIAS REQUIRE NON-CONDUCTIVE FILL AND PLANARIZE" at 10797.65,1135.52 h59
  text "XX MIL VIAS REQUIRE CONDUCTIVE FILL AND PLANARIZE" at 10805.65,1031.55 h60
  text "OUTER XX MIL TRACES REQUIRE 50 OHM SINGLE-ENDED IMPEDANCE" at 10804.66,868.16 h58
  text "LAYER 2 & 3 (INNER LAYERS) XX MIL WIDE, XX MIL SPACE / TRACES REQUIRE 100 OHM DIFFERENTIAL IMPEDANCE" at 10796.66,632.45 h60
  text ".Layer_Name" at -201.73,-1117.79 h60
M11 Gerber Information:
  lines w10: -1070.73,-1189.46 5529.27,-1189.46 ; -1070.73,-986.13 5531.27,-986.13 ; -1070.73,-782.8 -1070.73,-1392.8 2934.27,-1392.8 5531.27,-1392.8 5531.27,-782.8 -1070.23,-782.8 -1070.23,-1392.8 505.27,-1392.8 ; 1394.27,-1392.8 1394.27,-782.8 ; 2661.27,-986.13 2661.27,-782.8 ; 3501.27,-986.13 3501.27,-782.8 ; 4123.27,-1399.3 4123.27,-1196.46
  text "ALL ARTWORK VIEWED FROM TOP SIDE" at -1007.23,-914.96 h60
  text "BOARD #:" at 1469.27,-914.96 h60
  text ".PRJ_Number" at 2014.77,-914.96 h60
  text "REV:" at 2859.27,-914.96 h60
  text ".PCB_Rev" at 3150.77,-914.96 h60
  text "SVN REV:" at 3697.27,-914.96 h60
  text ".VersionControl_RevNumber" at 4203.27,-914.96 h60
  text "LAYER NAME =" at -1007.23,-1117.79 h60
  text "TID #:" at 1469.27,-1118.3 h60
  text ".TID" at 2014.77,-1118.3 h60
  text "PLOT NAME =" at -1007.23,-1323.63 h60
  text ".plot_File_Name" at -201.73,-1323.63 h60
  text "GENERATED    :" at 1471.27,-1323.63 h60
  text ".Print_Date" at 2340.77,-1323.63 h60
  text ".Print_Time" at 3069.77,-1323.63 h60
  text "TEXAS INSTRUMENTS" at 4334.27,-1323.63 h60
M12 Stackup:
  drawing of 295 lines, arcs and shapes, not listed
  text "Layer" at 4565.13,6105.01 h60
  text "Name" at 4975.04,6105.01 h60
  text "Material" at 5904.79,6105.01 h60
  text "Thickness" at 6764.56,6105.01 h60
  text "Constant" at 7414.39,6105.01 h60
  text "Board Layer Stack" at 7984.25,6105.01 h60
  text "Top Overlay" at 4975.04,5985.01 h60
  text "Top Solder" at 4975.04,5865.01 h60
  text "Solder Resist" at 5904.79,5865.01 h60
  text "0.40mil" at 6764.56,5865.01 h60
  text "3.5" at 7414.39,5865.01 h60
  text "1" at 4565.13,5745.01 h60
  text "Top Layer" at 4975.04,5745.01 h60
  text "1.40mil" at 6764.56,5745.01 h60
  text "Dielectric 1" at 4975.04,5625.01 h60
  text "FR-4" at 5904.79,5625.01 h60
  text "8.00mil" at 6764.56,5625.01 h60
  text "4.2" at 7414.39,5625.01 h60
  text "2" at 4565.13,5505.01 h60
  text "Ground" at 4975.04,5505.01 h60
  text "1.40mil" at 6764.56,5505.01 h60
  text "Dielectric 2" at 4975.04,5385.01 h60
  text "FR-4" at 5904.79,5385.01 h60
  text "40.00mil" at 6764.56,5385.01 h60
  text "4.2" at 7414.39,5385.01 h60
  text "3" at 4565.13,5265.01 h60
  text "Power" at 4975.04,5265.01 h60
  text "1.40mil" at 6764.56,5265.01 h60
  text "Dielectric 3" at 4975.04,5145.01 h60
  text "FR-4" at 5904.79,5145.01 h60
  text "8.00mil" at 6764.56,5145.01 h60
  text "4.2" at 7414.39,5145.01 h60
  text "4" at 4565.13,5025.01 h60
  text "Bottom Layer" at 4975.04,5025.01 h60
  text "1.40mil" at 6764.56,5025.01 h60
  text "Bottom Solder" at 4975.04,4905.01 h60
  text "Solder Resist" at 5904.79,4905.01 h60
  text "0.40mil" at 6764.56,4905.01 h60
  text "3.5" at 7414.39,4905.01 h60
  text "Bottom Overlay" at 4975.04,4785.01 h60
  text ".Layer_Name" at -201.73,-1117.79 h60
M13 Component Bodies Top:
  text ".Layer_Name" at -201.73,-1117.79 h60
M14 Component Bodies Bottom:
  text ".Layer_Name" at -201.73,-1117.79 h60
M15 Courtyards Top:
  text ".Layer_Name" at -201.73,-1117.79 h60
M16 Courtyards Bottom:
  text ".Layer_Name" at -201.73,-1117.79 h60
Drill Drawing:
  circle w10: c5239.83,3259.08 r16.58
  circle w10: c5239.83,3259.08 r27.63
  circle w10: c5239.83,3134.76 r27.63
  lines w10: 5212.2,2761.8 5239.83,2734.18 5267.45,2761.8 5239.83,2789.43 5212.2,2761.8 ; 5212.2,2872.31 5226.01,2872.31 5226.01,2858.5 5253.64,2858.5 5253.64,2872.31 5267.45,2872.31 5267.45,2899.94 5253.64,2899.94 5253.64,2913.75 5226.01,2913.75 5226.01,2899.94 5212.2,2899.94 5212.2,2872.31 ; 5212.2,2982.82 5267.45,2982.82 5267.45,3038.07 5212.2,3038.07 5212.2,2982.82 ; 5212.2,3355.78 5239.83,3369.59 5267.45,3355.78 5253.64,3383.4 5267.45,3411.03 5239.83,3397.22 5212.2,3411.03 5226.01,3383.4 5212.2,3355.78 ; 5212.2,3493.91 5226.01,3493.91 5239.83,3480.1 5253.64,3493.91 5267.45,3493.91 5253.64,3507.72 5267.45,3521.54 5253.64,3521.54 5239.83,3535.35 5226.01,3521.54 5212.2,3521.54 5226.01,3507.72 5212.2,3493.91 ; 5212.2,3659.67 5267.45,3659.67 5239.83,3604.42 5212.2,3659.67 ; 5212.2,3728.74 5212.2,3742.55 5226.01,3756.36 5212.2,3770.18 5212.2,3783.99 5226.01,3783.99 5239.83,3770.18 5253.64,3783.99 5267.45,3783.99 5267.45,3770.18 5253.64,3756.36 5267.45,3742.55 5267.45,3728.74 5253.64,3728.74 5239.83,3742.55 5226.01,3728.74 5212.2,3728.74 ; 5212.2,3853.06 5267.45,3853.06 5267.45,3908.31 5212.2,3908.31 5212.2,3853.06 ; 5223.25,3864.11 5256.4,3864.11 5256.4,3897.26 5223.25,3897.26 5223.25,3864.11
  lines w12: 5162.11,2696.88 8393.6,2696.88 ; 5162.11,3940.08 8393.6,3940.08 ; 5499.97,2572.56 5499.97,4064.4 ; 5831.97,2572.56 5831.97,4064.4 ; 6468.54,2572.56 6468.54,4064.4 ; 6727.68,2572.56 6727.68,4064.4 ; 7102.83,2572.56 7102.83,4064.4 ; 7827.17,2572.56 7827.17,4064.4 ; 5162.11,2572.56 8393.6,2572.56 8393.6,4064.4 5162.11,4064.4 5162.11,2572.56
  text "Symbol" at 5236.7,3977.38 h72
  text "Quantity" at 5537.27,3977.38 h72
  text "Finished Hole Size" at 5869.27,3977.38 h72
  text "Plated" at 6505.83,3977.38 h72
  text "Hole Type" at 6764.97,3977.38 h72
  text "Drill Layer Pair" at 7140.13,3977.38 h72
  text "Hole Tolerance" at 7864.46,3977.38 h72
  text "5" at 5537.27,3853.06 h60
  text "7.87mil (0.200mm)" at 5869.27,3853.06 h60
  text "PTH" at 6505.83,3853.06 h60
  text "Round" at 6764.97,3853.06 h60
  text "Top Layer - Bottom Layer" at 7140.13,3853.06 h60
  text "387" at 5537.27,3728.74 h60
  text "10.00mil (0.254mm)" at 5869.27,3728.74 h60
  text "PTH" at 6505.83,3728.74 h60
  text "Round" at 6764.97,3728.74 h60
  text "Top Layer - Bottom Layer" at 7140.13,3728.74 h60
  text "14" at 5537.27,3604.42 h60
  text "33.47mil (0.850mm)" at 5869.27,3604.42 h60
  text "PTH" at 6505.83,3604.42 h60
  text "Round" at 6764.97,3604.42 h60
  text "Top Layer - Bottom Layer" at 7140.13,3604.42 h60
  text "66" at 5537.27,3480.1 h60
  text "40.00mil (1.016mm)" at 5869.27,3480.1 h60
  text "PTH" at 6505.83,3480.1 h60
  text "Round" at 6764.97,3480.1 h60
  text "Top Layer - Bottom Layer" at 7140.13,3480.1 h60
  text "8" at 5537.27,3355.78 h60
  text "47.24mil (1.200mm)" at 5869.27,3355.78 h60
  text "PTH" at 6505.83,3355.78 h60
  text "Round" at 6764.97,3355.78 h60
  text "Top Layer - Bottom Layer" at 7140.13,3355.78 h60
  text "6" at 5537.27,3231.46 h60
  text "49.21mil (1.250mm)" at 5869.27,3231.46 h60
  text "PTH" at 6505.83,3231.46 h60
  text "Round" at 6764.97,3231.46 h60
  text "Top Layer - Bottom Layer" at 7140.13,3231.46 h60
  text "6" at 5537.27,3107.14 h60
  text "51.18mil (1.300mm)" at 5869.27,3107.14 h60
  text "PTH" at 6505.83,3107.14 h60
  text "Round" at 6764.97,3107.14 h60
  text "Top Layer - Bottom Layer" at 7140.13,3107.14 h60
  text "2" at 5537.27,2982.82 h60
  text "63.00mil (1.600mm)" at 5869.27,2982.82 h60
  text "PTH" at 6505.83,2982.82 h60
  text "Round" at 6764.97,2982.82 h60
  text "Top Layer - Bottom Layer" at 7140.13,2982.82 h60
  text "4" at 5537.27,2858.5 h60
  text "125.98mil (3.200mm)" at 5869.27,2858.5 h60
  text "PTH" at 6505.83,2858.5 h60
  text "Round" at 6764.97,2858.5 h60
  text "Top Layer - Bottom Layer" at 7140.13,2858.5 h60
  text "2" at 5537.27,2734.18 h60
  text "23.62mil (0.600mm)" at 5869.27,2734.18 h60
  text "PTH" at 6505.83,2734.18 h60
  text "Slot" at 6764.97,2734.18 h60
  text "Top Layer - Bottom Layer" at 7140.13,2734.18 h60
  text "500 Total" at 5537.27,2609.86 h60
  text "Slot definitions :" at 5236.7,2522.83 h60
  text "Routed Path Length" at 5687.42,2522.83 h60
  text "= Calculated from tool start centre position to tool end centre position." at 6227.16,2522.83 h60
  text "Hole Length" at 5687.42,2473.11 h60
  text "= Routed Path Length + Tool Size = Slot length as defined in the PCB layout" at 6027.36,2473.11 h60
  text ".Layer_Name" at -201.73,-1117.79 h60
Mechanical 17:
  text ".Layer_Name" at -201.73,-1117.79 h60
Mechanical 18:
  text ".Layer_Name" at -201.73,-1117.79 h60
Mechanical 19:
  text ".Layer_Name" at -201.73,-1117.79 h60

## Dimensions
-778.73,-659.3 to 221.27,-659.3 on M2 Board Dimensions
0,0 to 0,2850 on M2 Board Dimensions
0,0 to 4255,0 on M2 Board Dimensions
